VERSION 5.7 ;
BUSBITCHARS "[]" ;
DIVIDERCHAR "/" ;

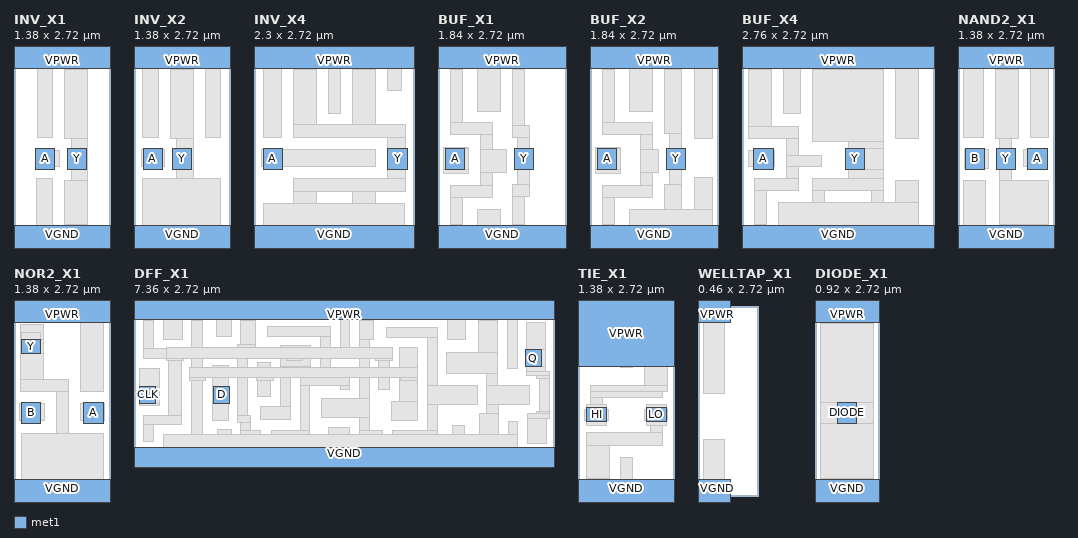
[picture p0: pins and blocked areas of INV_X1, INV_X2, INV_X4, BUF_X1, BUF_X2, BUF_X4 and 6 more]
MACRO INV_X1
  CLASS CORE ;
  ORIGIN 0 0 ;
  SIZE 1.380 BY 2.720 ;
  SYMMETRY X Y ;
  SITE unithd ;
  PIN A
    DIRECTION INPUT ;
    USE SIGNAL ;
    PORT
      LAYER met1 ;
        RECT 0.305 1.040 0.585 1.340 ;
    END
  END A
  PIN Y
    DIRECTION OUTPUT ;
    USE SIGNAL ;
    PORT
      LAYER met1 ;
        RECT 0.765 1.040 1.045 1.340 ;
    END
  END Y
  PIN VPWR
    DIRECTION INOUT ;
    USE POWER ;
    SHAPE ABUTMENT ;
    PORT
      LAYER met1 ;
        RECT 0.000 2.480 1.380 2.960 ;
    END
  END VPWR
  PIN VGND
    DIRECTION INOUT ;
    USE GROUND ;
    SHAPE ABUTMENT ;
    PORT
      LAYER met1 ;
        RECT 0.000 -0.240 1.380 0.240 ;
    END
  END VGND
  OBS
    LAYER li1 ;
      RECT 0.000 2.635 1.380 2.805 ;
      RECT 0.340 1.495 0.550 2.635 ;
      RECT 0.720 0.255 1.050 0.885 ;
      RECT 0.720 1.485 1.050 2.465 ;
      RECT 0.820 0.885 1.050 1.040 ;
      RECT 0.820 1.340 1.050 1.485 ;
      RECT 1.045 1.040 1.050 1.340 ;
      RECT 0.585 1.075 0.650 1.315 ;
      RECT 0.000 -0.085 1.380 0.085 ;
      RECT 0.320 0.085 0.550 0.905 ;
  END
END INV_X1

MACRO INV_X2
  CLASS CORE ;
  ORIGIN 0 0 ;
  SIZE 1.380 BY 2.720 ;
  SYMMETRY X Y ;
  SITE unithd ;
  PIN A
    DIRECTION INPUT ;
    USE SIGNAL ;
    PORT
      LAYER met1 ;
        RECT 0.130 1.040 0.410 1.340 ;
    END
  END A
  PIN Y
    DIRECTION OUTPUT ;
    USE SIGNAL ;
    PORT
      LAYER met1 ;
        RECT 0.550 1.040 0.830 1.340 ;
    END
  END Y
  PIN VPWR
    DIRECTION INOUT ;
    USE POWER ;
    SHAPE ABUTMENT ;
    PORT
      LAYER met1 ;
        RECT 0.000 2.480 1.380 2.960 ;
    END
  END VPWR
  PIN VGND
    DIRECTION INOUT ;
    USE GROUND ;
    SHAPE ABUTMENT ;
    PORT
      LAYER met1 ;
        RECT 0.000 -0.240 1.380 0.240 ;
    END
  END VGND
  OBS
    LAYER li1 ;
      RECT 0.000 2.635 1.380 2.805 ;
      RECT 0.125 1.495 0.355 2.635 ;
      RECT 1.025 1.495 1.235 2.635 ;
      RECT 0.525 0.255 0.855 0.885 ;
      RECT 0.525 1.485 0.855 2.465 ;
      RECT 0.605 0.885 0.855 1.040 ;
      RECT 0.605 1.340 0.855 1.485 ;
      RECT 0.830 1.040 0.855 1.340 ;
      RECT 0.105 1.075 0.130 1.325 ;
      RECT 0.410 1.075 0.435 1.325 ;
      RECT 0.000 -0.085 1.380 0.085 ;
      RECT 0.125 0.085 1.235 0.905 ;
  END
END INV_X2

MACRO INV_X4
  CLASS CORE ;
  ORIGIN 0 0 ;
  SIZE 2.300 BY 2.720 ;
  SYMMETRY X Y ;
  SITE unithd ;
  PIN A
    DIRECTION INPUT ;
    USE SIGNAL ;
    PORT
      LAYER met1 ;
        RECT 0.130 1.040 0.410 1.340 ;
    END
  END A
  PIN Y
    DIRECTION OUTPUT ;
    USE SIGNAL ;
    PORT
      LAYER met1 ;
        RECT 1.915 1.040 2.195 1.340 ;
    END
  END Y
  PIN VPWR
    DIRECTION INOUT ;
    USE POWER ;
    SHAPE ABUTMENT ;
    PORT
      LAYER met1 ;
        RECT 0.000 2.480 2.300 2.960 ;
    END
  END VPWR
  PIN VGND
    DIRECTION INOUT ;
    USE GROUND ;
    SHAPE ABUTMENT ;
    PORT
      LAYER met1 ;
        RECT 0.000 -0.240 2.300 0.240 ;
    END
  END VGND
  OBS
    LAYER li1 ;
      RECT 0.000 2.635 2.300 2.805 ;
      RECT 0.130 1.495 0.395 2.635 ;
      RECT 1.905 2.175 2.115 2.635 ;
      RECT 1.065 1.835 1.235 2.635 ;
      RECT 0.565 0.255 0.895 0.725 ;
      RECT 0.565 0.725 2.170 0.905 ;
      RECT 0.565 1.495 2.170 1.685 ;
      RECT 0.565 1.685 0.895 2.465 ;
      RECT 1.405 0.255 1.735 0.725 ;
      RECT 1.405 1.685 1.735 2.465 ;
      RECT 1.905 0.905 2.170 1.040 ;
      RECT 1.905 1.040 1.915 1.340 ;
      RECT 1.905 1.340 2.170 1.495 ;
      RECT 0.105 1.075 0.130 1.325 ;
      RECT 0.410 1.075 1.735 1.325 ;
      RECT 0.000 -0.085 2.300 0.085 ;
      RECT 0.130 0.085 2.155 0.545 ;
      RECT 1.905 0.545 2.155 0.550 ;
  END
END INV_X4

MACRO BUF_X1
  CLASS CORE ;
  ORIGIN 0 0 ;
  SIZE 1.840 BY 2.720 ;
  SYMMETRY X Y ;
  SITE unithd ;
  PIN A
    DIRECTION INPUT ;
    USE SIGNAL ;
    PORT
      LAYER met1 ;
        RECT 0.105 1.040 0.385 1.340 ;
    END
  END A
  PIN Y
    DIRECTION OUTPUT ;
    USE SIGNAL ;
    PORT
      LAYER met1 ;
        RECT 1.090 1.040 1.370 1.340 ;
    END
  END Y
  PIN VPWR
    DIRECTION INOUT ;
    USE POWER ;
    SHAPE ABUTMENT ;
    PORT
      LAYER met1 ;
        RECT 0.000 2.480 1.840 2.960 ;
    END
  END VPWR
  PIN VGND
    DIRECTION INOUT ;
    USE GROUND ;
    SHAPE ABUTMENT ;
    PORT
      LAYER met1 ;
        RECT 0.000 -0.240 1.840 0.240 ;
    END
  END VGND
  OBS
    LAYER li1 ;
      RECT 0.000 2.635 1.840 2.805 ;
      RECT 0.560 1.875 0.890 2.635 ;
      RECT 0.175 0.255 0.345 0.635 ;
      RECT 0.175 0.635 0.780 0.805 ;
      RECT 0.175 1.535 0.780 1.705 ;
      RECT 0.175 1.705 0.345 2.465 ;
      RECT 0.610 0.805 0.780 0.995 ;
      RECT 0.610 0.995 0.975 1.325 ;
      RECT 0.610 1.325 0.780 1.535 ;
      RECT 1.070 1.495 1.315 1.665 ;
      RECT 1.070 1.665 1.240 2.465 ;
      RECT 1.145 1.340 1.315 1.495 ;
      RECT 0.085 0.985 0.440 1.040 ;
      RECT 0.085 1.040 0.105 1.340 ;
      RECT 0.085 1.340 0.440 1.355 ;
      RECT 0.385 1.040 0.440 1.340 ;
      RECT 1.070 0.255 1.240 0.655 ;
      RECT 1.070 0.655 1.315 0.825 ;
      RECT 1.145 0.825 1.315 1.040 ;
      RECT 0.000 -0.085 1.840 0.085 ;
      RECT 0.560 0.085 0.890 0.465 ;
  END
END BUF_X1

MACRO BUF_X2
  CLASS CORE ;
  ORIGIN 0 0 ;
  SIZE 1.840 BY 2.720 ;
  SYMMETRY X Y ;
  SITE unithd ;
  PIN A
    DIRECTION INPUT ;
    USE SIGNAL ;
    PORT
      LAYER met1 ;
        RECT 0.105 1.040 0.385 1.340 ;
    END
  END A
  PIN Y
    DIRECTION OUTPUT ;
    USE SIGNAL ;
    PORT
      LAYER met1 ;
        RECT 1.090 1.040 1.370 1.340 ;
    END
  END Y
  PIN VPWR
    DIRECTION INOUT ;
    USE POWER ;
    SHAPE ABUTMENT ;
    PORT
      LAYER met1 ;
        RECT 0.000 2.480 1.840 2.960 ;
    END
  END VPWR
  PIN VGND
    DIRECTION INOUT ;
    USE GROUND ;
    SHAPE ABUTMENT ;
    PORT
      LAYER met1 ;
        RECT 0.000 -0.240 1.840 0.240 ;
    END
  END VGND
  OBS
    LAYER li1 ;
      RECT 0.000 2.635 1.840 2.805 ;
      RECT 0.560 1.875 0.890 2.635 ;
      RECT 1.490 1.485 1.750 2.635 ;
      RECT 0.175 0.255 0.345 0.635 ;
      RECT 0.175 0.635 0.890 0.805 ;
      RECT 0.175 1.535 0.890 1.705 ;
      RECT 0.175 1.705 0.345 2.465 ;
      RECT 0.720 0.805 0.890 0.995 ;
      RECT 0.720 0.995 0.975 1.325 ;
      RECT 0.720 1.325 0.890 1.535 ;
      RECT 1.060 1.560 1.315 2.465 ;
      RECT 1.145 1.340 1.315 1.560 ;
      RECT 0.085 0.985 0.440 1.040 ;
      RECT 0.085 1.040 0.105 1.340 ;
      RECT 0.085 1.340 0.440 1.355 ;
      RECT 0.385 1.040 0.440 1.340 ;
      RECT 1.060 0.255 1.315 0.830 ;
      RECT 1.145 0.830 1.315 1.040 ;
      RECT 0.000 -0.085 1.840 0.085 ;
      RECT 0.560 0.085 1.750 0.465 ;
      RECT 1.490 0.465 1.750 0.925 ;
  END
END BUF_X2

MACRO BUF_X4
  CLASS CORE ;
  ORIGIN 0 0 ;
  SIZE 2.760 BY 2.720 ;
  SYMMETRY X Y ;
  SITE unithd ;
  PIN A
    DIRECTION INPUT ;
    USE SIGNAL ;
    PORT
      LAYER met1 ;
        RECT 0.165 1.040 0.445 1.340 ;
    END
  END A
  PIN Y
    DIRECTION OUTPUT ;
    USE SIGNAL ;
    PORT
      LAYER met1 ;
        RECT 1.475 1.040 1.755 1.340 ;
    END
  END Y
  PIN VPWR
    DIRECTION INOUT ;
    USE POWER ;
    SHAPE ABUTMENT ;
    PORT
      LAYER met1 ;
        RECT 0.000 2.480 2.760 2.960 ;
    END
  END VPWR
  PIN VGND
    DIRECTION INOUT ;
    USE GROUND ;
    SHAPE ABUTMENT ;
    PORT
      LAYER met1 ;
        RECT 0.000 -0.240 2.760 0.240 ;
    END
  END VGND
  OBS
    LAYER li1 ;
      RECT 0.000 2.635 2.760 2.805 ;
      RECT 0.595 1.835 0.835 2.635 ;
      RECT 2.195 1.485 2.525 2.635 ;
      RECT 1.355 1.835 1.685 2.635 ;
      RECT 0.095 1.485 0.810 1.655 ;
      RECT 0.095 1.655 0.425 2.465 ;
      RECT 0.175 0.255 0.345 0.735 ;
      RECT 0.175 0.735 0.810 0.905 ;
      RECT 0.640 0.905 0.810 1.075 ;
      RECT 0.640 1.075 1.140 1.245 ;
      RECT 0.640 1.245 0.810 1.485 ;
      RECT 1.015 0.255 1.185 0.735 ;
      RECT 1.015 0.735 2.025 0.905 ;
      RECT 1.015 1.445 2.025 2.465 ;
      RECT 1.530 0.905 2.025 1.040 ;
      RECT 1.530 1.340 2.025 1.445 ;
      RECT 1.755 1.040 2.025 1.340 ;
      RECT 1.855 0.255 2.025 0.735 ;
      RECT 0.090 1.075 0.165 1.315 ;
      RECT 0.445 1.075 0.470 1.315 ;
      RECT 0.000 -0.085 2.760 0.085 ;
      RECT 0.525 0.085 2.525 0.565 ;
      RECT 2.195 0.565 2.525 0.885 ;
  END
END BUF_X4

MACRO NAND2_X1
  CLASS CORE ;
  ORIGIN 0 0 ;
  SIZE 1.380 BY 2.720 ;
  SYMMETRY X Y ;
  SITE unithd ;
  PIN A
    DIRECTION INPUT ;
    USE SIGNAL ;
    PORT
      LAYER met1 ;
        RECT 0.995 1.040 1.275 1.340 ;
    END
  END A
  PIN B
    DIRECTION INPUT ;
    USE SIGNAL ;
    PORT
      LAYER met1 ;
        RECT 0.105 1.040 0.385 1.340 ;
    END
  END B
  PIN Y
    DIRECTION OUTPUT ;
    USE SIGNAL ;
    PORT
      LAYER met1 ;
        RECT 0.545 1.040 0.825 1.340 ;
    END
  END Y
  PIN VPWR
    DIRECTION INOUT ;
    USE POWER ;
    SHAPE ABUTMENT ;
    PORT
      LAYER met1 ;
        RECT 0.000 2.480 1.380 2.960 ;
    END
  END VPWR
  PIN VGND
    DIRECTION INOUT ;
    USE GROUND ;
    SHAPE ABUTMENT ;
    PORT
      LAYER met1 ;
        RECT 0.000 -0.240 1.380 0.240 ;
    END
  END VGND
  OBS
    LAYER li1 ;
      RECT 0.000 2.635 1.380 2.805 ;
      RECT 0.085 1.495 0.365 2.635 ;
      RECT 1.035 1.495 1.295 2.635 ;
      RECT 0.535 1.485 0.865 2.465 ;
      RECT 0.600 1.340 0.770 1.485 ;
      RECT 0.095 1.055 0.105 1.325 ;
      RECT 0.940 1.075 0.995 1.325 ;
      RECT 0.385 1.055 0.430 1.325 ;
      RECT 0.600 0.255 1.295 0.885 ;
      RECT 0.600 0.885 0.770 1.040 ;
      RECT 0.000 -0.085 1.380 0.085 ;
      RECT 0.085 0.085 0.395 0.885 ;
  END
END NAND2_X1

MACRO NOR2_X1
  CLASS CORE ;
  ORIGIN 0 0 ;
  SIZE 1.380 BY 2.720 ;
  SYMMETRY X Y ;
  SITE unithd ;
  PIN A
    DIRECTION INPUT ;
    USE SIGNAL ;
    PORT
      LAYER met1 ;
        RECT 0.995 1.040 1.275 1.340 ;
    END
  END A
  PIN B
    DIRECTION INPUT ;
    USE SIGNAL ;
    PORT
      LAYER met1 ;
        RECT 0.105 1.040 0.385 1.340 ;
    END
  END B
  PIN Y
    DIRECTION OUTPUT ;
    USE SIGNAL ;
    PORT
      LAYER met1 ;
        RECT 0.105 2.040 0.385 2.240 ;
    END
  END Y
  PIN VPWR
    DIRECTION INOUT ;
    USE POWER ;
    SHAPE ABUTMENT ;
    PORT
      LAYER met1 ;
        RECT 0.000 2.480 1.380 2.960 ;
    END
  END VPWR
  PIN VGND
    DIRECTION INOUT ;
    USE GROUND ;
    SHAPE ABUTMENT ;
    PORT
      LAYER met1 ;
        RECT 0.000 -0.240 1.380 0.240 ;
    END
  END VGND
  OBS
    LAYER li1 ;
      RECT 0.000 2.635 1.380 2.805 ;
      RECT 0.955 1.495 1.285 2.635 ;
      RECT 0.095 1.495 0.775 1.665 ;
      RECT 0.095 1.665 0.425 2.040 ;
      RECT 0.095 2.040 0.105 2.240 ;
      RECT 0.095 2.240 0.425 2.450 ;
      RECT 0.385 2.040 0.425 2.240 ;
      RECT 0.515 0.255 0.845 0.895 ;
      RECT 0.605 0.895 0.775 1.495 ;
      RECT 0.085 1.075 0.105 1.325 ;
      RECT 0.945 1.075 0.995 1.325 ;
      RECT 1.275 1.075 1.295 1.325 ;
      RECT 0.385 1.075 0.435 1.325 ;
      RECT 0.000 -0.085 1.380 0.085 ;
      RECT 0.105 0.085 1.285 0.895 ;
    LAYER met1 ;
      RECT 0.105 2.240 0.385 2.340 ;
  END
END NOR2_X1

MACRO DFF_X1
  CLASS CORE ;
  ORIGIN 0 0 ;
  SIZE 7.360 BY 2.720 ;
  SYMMETRY X Y ;
  SITE unithd ;
  PIN CLK
    DIRECTION INPUT ;
    USE SIGNAL ;
    PORT
      LAYER met1 ;
        RECT 0.105 1.010 0.385 1.310 ;
    END
  END CLK
  PIN D
    DIRECTION INPUT ;
    USE SIGNAL ;
    PORT
      LAYER met1 ;
        RECT 1.395 1.010 1.675 1.310 ;
    END
  END D
  PIN Q
    DIRECTION OUTPUT ;
    USE SIGNAL ;
    PORT
      LAYER met1 ;
        RECT 6.860 1.650 7.140 1.950 ;
    END
  END Q
  PIN VPWR
    DIRECTION INOUT ;
    USE POWER ;
    SHAPE ABUTMENT ;
    PORT
      LAYER met1 ;
        RECT 0.000 2.480 7.360 2.960 ;
    END
  END VPWR
  PIN VGND
    DIRECTION INOUT ;
    USE GROUND ;
    SHAPE ABUTMENT ;
    PORT
      LAYER met1 ;
        RECT 0.000 -0.240 7.360 0.240 ;
    END
  END VGND
  OBS
    LAYER li1 ;
      RECT 0.000 2.635 7.360 2.805 ;
      RECT 0.515 2.135 0.845 2.635 ;
      RECT 1.440 2.175 1.705 2.635 ;
      RECT 3.610 1.835 3.780 2.635 ;
      RECT 5.490 2.135 5.805 2.635 ;
      RECT 6.545 1.625 6.715 2.635 ;
      RECT 1.015 0.345 1.200 2.465 ;
      RECT 5.480 1.530 6.375 1.905 ;
      RECT 6.035 1.905 6.375 2.465 ;
      RECT 6.055 0.300 6.385 0.825 ;
      RECT 6.185 0.825 6.385 0.995 ;
      RECT 6.185 0.995 6.935 1.325 ;
      RECT 6.185 1.325 6.375 1.530 ;
      RECT 0.175 0.345 0.345 0.635 ;
      RECT 0.175 0.635 0.840 0.805 ;
      RECT 0.175 1.795 0.840 1.965 ;
      RECT 0.175 1.965 0.345 2.465 ;
      RECT 0.610 0.805 0.840 1.795 ;
      RECT 1.820 0.675 2.045 0.805 ;
      RECT 1.820 0.805 1.990 1.910 ;
      RECT 1.820 1.910 2.125 2.040 ;
      RECT 1.875 0.365 2.210 0.535 ;
      RECT 1.875 0.535 2.045 0.675 ;
      RECT 1.875 2.040 2.125 2.465 ;
      RECT 3.290 0.765 4.120 1.095 ;
      RECT 3.950 0.365 4.355 0.535 ;
      RECT 3.950 0.535 4.120 0.765 ;
      RECT 3.950 1.095 4.120 2.135 ;
      RECT 3.950 2.135 4.200 2.465 ;
      RECT 6.885 1.495 7.275 1.575 ;
      RECT 6.885 1.575 7.215 1.650 ;
      RECT 6.885 1.950 7.215 2.420 ;
      RECT 6.895 0.305 7.225 0.740 ;
      RECT 6.895 0.740 7.275 0.825 ;
      RECT 7.050 0.825 7.275 0.865 ;
      RECT 7.060 1.445 7.275 1.495 ;
      RECT 7.105 0.865 7.275 1.445 ;
      RECT 7.140 1.650 7.215 1.950 ;
      RECT 2.335 2.190 3.440 2.360 ;
      RECT 2.405 0.365 3.080 0.535 ;
      RECT 2.910 0.535 3.080 1.315 ;
      RECT 2.910 1.315 3.780 1.485 ;
      RECT 3.270 1.485 3.780 1.575 ;
      RECT 3.270 1.575 3.440 2.190 ;
      RECT 3.610 1.245 3.780 1.315 ;
      RECT 4.425 2.165 5.310 2.335 ;
      RECT 4.525 0.365 5.310 0.535 ;
      RECT 5.140 0.535 5.310 0.995 ;
      RECT 5.140 0.995 6.015 1.325 ;
      RECT 5.140 1.325 5.310 2.165 ;
      RECT 2.215 0.735 2.740 0.955 ;
      RECT 2.570 0.955 2.740 1.655 ;
      RECT 2.570 1.655 3.100 2.020 ;
      RECT 4.505 0.705 4.970 1.035 ;
      RECT 4.650 1.035 4.970 1.995 ;
      RECT 4.290 1.245 4.480 1.965 ;
      RECT 2.160 1.125 2.400 1.720 ;
      RECT 1.370 0.715 1.650 1.010 ;
      RECT 1.370 1.010 1.395 1.310 ;
      RECT 1.370 1.310 1.650 1.665 ;
      RECT 0.090 0.975 0.440 1.010 ;
      RECT 0.090 1.010 0.105 1.310 ;
      RECT 0.090 1.310 0.440 1.625 ;
      RECT 0.385 1.010 0.440 1.310 ;
      RECT 0.000 -0.085 7.360 0.085 ;
      RECT 0.515 0.085 6.725 0.465 ;
      RECT 1.455 0.465 1.705 0.545 ;
      RECT 3.400 0.465 3.770 0.585 ;
      RECT 5.585 0.465 5.795 0.615 ;
      RECT 6.555 0.465 6.725 0.695 ;
    LAYER met1 ;
      RECT 0.570 1.755 0.860 1.800 ;
      RECT 0.570 1.800 4.530 1.985 ;
      RECT 2.670 1.755 2.960 1.800 ;
      RECT 4.240 1.755 4.530 1.800 ;
      RECT 0.965 1.415 1.255 1.460 ;
      RECT 0.965 1.460 4.965 1.645 ;
      RECT 2.155 1.415 2.445 1.460 ;
      RECT 4.675 1.415 4.965 1.460 ;
  END
END DFF_X1

MACRO TIE_X1
  CLASS CORE ;
  ORIGIN 0 0 ;
  SIZE 1.380 BY 2.720 ;
  SYMMETRY X Y ;
  SITE unithd ;
  PIN HI
    DIRECTION OUTPUT ;
    USE SIGNAL ;
    PORT
      LAYER met1 ;
        RECT 0.125 1.060 0.405 1.260 ;
    END
  END HI
  PIN LO
    DIRECTION OUTPUT ;
    USE SIGNAL ;
    PORT
      LAYER met1 ;
        RECT 0.980 1.060 1.260 1.260 ;
    END
  END LO
  PIN VPWR
    DIRECTION INOUT ;
    USE POWER ;
    SHAPE ABUTMENT ;
    PORT
      LAYER met1 ;
        RECT 0.000 1.855 1.380 2.960 ;
    END
  END VPWR
  PIN VGND
    DIRECTION INOUT ;
    USE GROUND ;
    SHAPE ABUTMENT ;
    PORT
      LAYER met1 ;
        RECT 0.000 -0.240 1.380 0.240 ;
    END
  END VGND
  OBS
    LAYER li1 ;
      RECT 0.000 2.635 1.380 2.805 ;
      RECT 0.180 1.260 0.350 1.415 ;
      RECT 0.180 1.415 1.205 1.495 ;
      RECT 0.180 1.495 1.285 1.585 ;
      RECT 0.955 1.585 1.285 2.465 ;
      RECT 0.615 1.835 0.785 2.165 ;
      RECT 0.405 1.075 0.435 1.245 ;
      RECT 0.095 1.075 0.125 1.245 ;
      RECT 0.955 1.075 0.980 1.245 ;
      RECT 1.260 1.075 1.285 1.245 ;
      RECT 0.115 0.255 0.445 0.720 ;
      RECT 0.115 0.720 1.205 0.905 ;
      RECT 1.035 0.905 1.205 1.060 ;
      RECT 0.000 -0.085 1.380 0.085 ;
      RECT 0.615 0.085 0.785 0.550 ;
    LAYER met1 ;
      RECT 0.125 1.260 0.405 1.310 ;
      RECT 0.980 1.260 1.260 1.310 ;
      RECT 0.980 1.010 1.260 1.060 ;
      RECT 0.125 1.010 0.405 1.060 ;
  END
END TIE_X1

MACRO WELLTAP_X1
  CLASS CORE WELLTAP ;
  ORIGIN 0 0 ;
  SIZE 0.460 BY 2.720 ;
  SYMMETRY X Y ;
  SITE unithd ;
  PIN VPWR
    DIRECTION INOUT ;
    USE POWER ;
    SHAPE ABUTMENT ;
    PORT
      LAYER met1 ;
        RECT 0.000 2.480 0.460 2.960 ;
    END
  END VPWR
  PIN VGND
    DIRECTION INOUT ;
    USE GROUND ;
    SHAPE ABUTMENT ;
    PORT
      LAYER met1 ;
        RECT 0.000 -0.240 0.460 0.240 ;
    END
  END VGND
  OBS
    LAYER li1 ;
      RECT 0.000 2.635 0.460 2.805 ;
      RECT 0.085 1.470 0.375 2.635 ;
      RECT 0.000 -0.085 0.460 0.085 ;
      RECT 0.085 0.085 0.375 0.810 ;
  END
END WELLTAP_X1

MACRO DIODE_X1
  CLASS CORE ANTENNACELL ;
  ORIGIN 0 0 ;
  SIZE 0.920 BY 2.720 ;
  SYMMETRY X Y ;
  SITE unithd ;
  PIN DIODE
    DIRECTION INPUT ;
    USE SIGNAL ;
    ANTENNADIFFAREA 0.4347 ;
    PORT
      LAYER met1 ;
        RECT 0.320 1.040 0.600 1.340 ;
    END
  END DIODE
  PIN VPWR
    DIRECTION INOUT ;
    USE POWER ;
    SHAPE ABUTMENT ;
    PORT
      LAYER met1 ;
        RECT 0.000 2.480 0.920 2.960 ;
    END
  END VPWR
  PIN VGND
    DIRECTION INOUT ;
    USE GROUND ;
    SHAPE ABUTMENT ;
    PORT
      LAYER met1 ;
        RECT 0.000 -0.240 0.920 0.240 ;
    END
  END VGND
  OBS
    LAYER li1 ;
      RECT 0.000 2.635 0.920 2.805 ;
      RECT 0.085 0.255 0.835 1.040 ;
      RECT 0.085 1.040 0.320 1.340 ;
      RECT 0.085 1.340 0.835 2.465 ;
      RECT 0.600 1.040 0.835 1.340 ;
      RECT 0.000 -0.085 0.920 0.085 ;
  END
END DIODE_X1

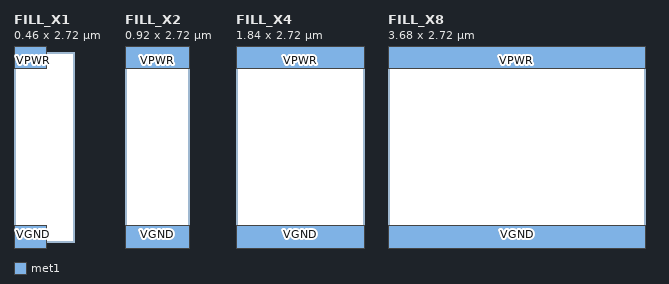
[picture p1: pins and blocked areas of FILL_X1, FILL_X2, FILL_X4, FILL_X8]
MACRO FILL_X1
  CLASS CORE SPACER ;
  ORIGIN 0 0 ;
  SIZE 0.460 BY 2.720 ;
  SYMMETRY X Y ;
  SITE unithd ;
  PIN VPWR
    DIRECTION INOUT ;
    USE POWER ;
    SHAPE ABUTMENT ;
    PORT
      LAYER met1 ;
        RECT 0.000 2.480 0.460 2.960 ;
    END
  END VPWR
  PIN VGND
    DIRECTION INOUT ;
    USE GROUND ;
    SHAPE ABUTMENT ;
    PORT
      LAYER met1 ;
        RECT 0.000 -0.240 0.460 0.240 ;
    END
  END VGND
  OBS
    LAYER li1 ;
      RECT 0.000 2.635 0.460 2.805 ;
      RECT 0.000 -0.085 0.460 0.085 ;
  END
END FILL_X1

MACRO FILL_X2
  CLASS CORE SPACER ;
  ORIGIN 0 0 ;
  SIZE 0.920 BY 2.720 ;
  SYMMETRY X Y ;
  SITE unithd ;
  PIN VPWR
    DIRECTION INOUT ;
    USE POWER ;
    SHAPE ABUTMENT ;
    PORT
      LAYER met1 ;
        RECT 0.000 2.480 0.920 2.960 ;
    END
  END VPWR
  PIN VGND
    DIRECTION INOUT ;
    USE GROUND ;
    SHAPE ABUTMENT ;
    PORT
      LAYER met1 ;
        RECT 0.000 -0.240 0.920 0.240 ;
    END
  END VGND
  OBS
    LAYER li1 ;
      RECT 0.000 2.635 0.920 2.805 ;
      RECT 0.000 -0.085 0.920 0.085 ;
  END
END FILL_X2

MACRO FILL_X4
  CLASS CORE SPACER ;
  ORIGIN 0 0 ;
  SIZE 1.840 BY 2.720 ;
  SYMMETRY X Y ;
  SITE unithd ;
  PIN VPWR
    DIRECTION INOUT ;
    USE POWER ;
    SHAPE ABUTMENT ;
    PORT
      LAYER met1 ;
        RECT 0.000 2.480 1.840 2.960 ;
    END
  END VPWR
  PIN VGND
    DIRECTION INOUT ;
    USE GROUND ;
    SHAPE ABUTMENT ;
    PORT
      LAYER met1 ;
        RECT 0.000 -0.240 1.840 0.240 ;
    END
  END VGND
  OBS
    LAYER li1 ;
      RECT 0.000 2.635 1.840 2.805 ;
      RECT 0.000 -0.085 1.840 0.085 ;
  END
END FILL_X4

MACRO FILL_X8
  CLASS CORE SPACER ;
  ORIGIN 0 0 ;
  SIZE 3.680 BY 2.720 ;
  SYMMETRY X Y ;
  SITE unithd ;
  PIN VPWR
    DIRECTION INOUT ;
    USE POWER ;
    SHAPE ABUTMENT ;
    PORT
      LAYER met1 ;
        RECT 0.000 2.480 3.680 2.960 ;
    END
  END VPWR
  PIN VGND
    DIRECTION INOUT ;
    USE GROUND ;
    SHAPE ABUTMENT ;
    PORT
      LAYER met1 ;
        RECT 0.000 -0.240 3.680 0.240 ;
    END
  END VGND
  OBS
    LAYER li1 ;
      RECT 0.000 2.635 3.680 2.805 ;
      RECT 0.000 -0.085 3.680 0.085 ;
  END
END FILL_X8

END LIBRARY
